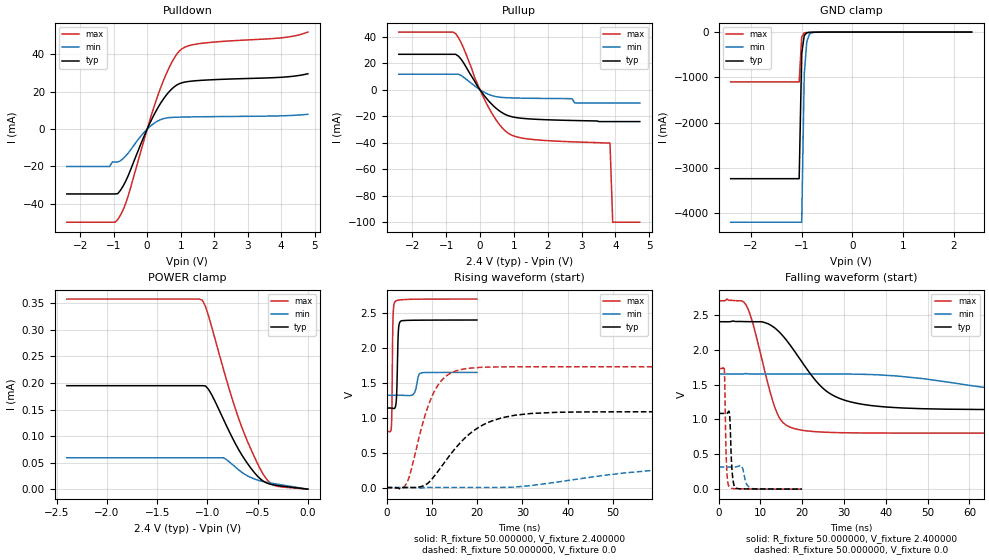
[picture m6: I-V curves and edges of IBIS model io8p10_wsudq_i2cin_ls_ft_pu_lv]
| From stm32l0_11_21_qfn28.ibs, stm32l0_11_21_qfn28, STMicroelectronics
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|   Model io8p10_wsudq_i2cin_ls_ft_pu_lv
[Model]  io8p10_wsudq_i2cin_ls_ft_pu_lv
Model_type I/O
Polarity   Non-Inverting
Enable   Active-Low
Vinl =   0.720000V
Vinh =   1.680000V
Vmeas =  1.200000V
Cref =   50.000000pF
Rref =   100.000000M
Vref =   0.0V
C_comp   2.943600pF   2.919700pF   2.965100pF
[Temperature Range]   25.000000   0.105000k   -40.000000
[Pullup Reference]   2.400000V   1.650000V   2.700000V
[Pulldown Reference]   0.0V   0.0V   0.0V
[POWER Clamp Reference]   2.400000V   1.650000V   2.700000V
[GND Clamp Reference]   0.0V   0.0V   0.0V
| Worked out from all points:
|   slope of the pulldown table from 0 to 0.36 V, typ, clamps not added: 28.5 ohm
|   slope of the pullup table from 0 to 0.36 V, typ, clamps not added: 32.2 ohm
|   GND clamp passes 1 mA (typ) near -0.65 V on its own axis
|   rising waveform, R_fixture 50.000000, V_fixture 2.400000: 20-80 % time 285ps typ, 637ps min, 195ps max; typ from 1.14 V to 2.4 V
|   rising waveform, R_fixture 50.000000, V_fixture 0.0: 20-80 % time 9.34ns typ, 24.6ns min, 4.81ns max; typ from 0.001 V to 1.09 V
|   falling waveform, R_fixture 50.000000, V_fixture 2.400000: 20-80 % time 10ns typ, 27.9ns min, 4.95ns max; typ from 2.4 V to 1.14 V
|   falling waveform, R_fixture 50.000000, V_fixture 0.0: 20-80 % time 486ps typ, 847ps min, 387ps max; typ from 1.09 V to 0.001 V
[Pulldown]
|Voltage   I(typ)   I(min)   I(max)
-2.4V     -34.7mA    -20mA      -49.82mA
-1.12V    -34.7mA    -20mA      -49.82mA
-1.04V    -34.7mA    -17.61mA   -49.82mA
-880mV    -34.55mA   -17.61mA   -48.46mA
-560mV    -24.65mA   -12.68mA   -35.33mA
0V        0A         0A         0A
400mV     13.84mA    5.066mA    22.03mA
720mV     21.25mA    6.254mA    35.26mA
1.04V     24.83mA    6.464mA    43.02mA
1.6V      26.11mA    6.627mA    45.88mA
4V        27.76mA    7.125mA    48.87mA
4.8V      29.63mA    7.94mA     51.96mA
[Pullup]
|Voltage   I(typ)   I(min)   I(max)
-2.4V     26.83mA    11.83mA    43.61mA
-720mV    26.83mA    11.83mA    42.44mA
-480mV    20.19mA    9.416mA    31.24mA
-160mV    6.617mA    3.074mA    9.467mA
240mV     -7.917mA   -3.299mA   -12.65mA
560mV     -15.67mA   -5.497mA   -25.76mA
880mV     -19.92mA   -6.062mA   -33.51mA
1.68V     -22.29mA   -6.449mA   -37.81mA
2.8V      -23.2mA    -10mA      -39.35mA
3.84V     -24mA      -10mA      -40.2mA
3.92V     -24mA      -10mA      -100mA
4.72V     -24mA      -10mA      -100mA
[GND_clamp]
|Voltage   I(typ)   I(min)   I(max)
-2.4V     -3.237A    -4.198A    -1.1A
-1.05V    -3.237A    -4.198A    -1.1A
-1V       -475.8mA   -4.198A    -104.2mA
-950mV    -76.24mA   -935.4mA   -18.39mA
-900mV    -16.61mA   -212.9mA   -9.105mA
-850mV    -6.547mA   -50.94mA   -6.589mA
-800mV    -3.998mA   -13.81mA   -4.86mA
-650mV    -1.043mA   -1.182mA   -1.146mA
2.35V     0A         0A         0A
[POWER_clamp]
|Voltage   I(typ)   I(min)   I(max)
-2.4V     195uA      59.14uA    358.2uA
-1.05V    195uA      59.14uA    356uA
-1.02V    194.5uA    59.14uA    344.5uA
-960mV    178.7uA    59.14uA    307.4uA
-840mV    131.4uA    59.14uA    225.5uA
-690mV    74.82uA    36.58uA    133.7uA
-600mV    48.08uA    24.92uA    89.53uA
-510mV    26.23uA    17.69uA    51.64uA
-450mV    15.91uA    14.53uA    29.77uA
-390mV    10.19uA    12.23uA    14.39uA
-330mV    7.608uA    10.24uA    6.963uA
0V        0A         0A         0A
[Ramp]
| variable   typ   min   max
dV/dt_r  0.65095/9.32887n   0.19037/24.57509n   1.03799/4.79707n
dV/dt_f  0.75618/10.03745n   0.19644/27.86319n   1.13779/4.93680n
R_load = 50.000000
[Rising Waveform]
R_fixture= 50.000000
V_fixture= 2.400000
V_fixture_min= 1.650000
V_fixture_max= 2.700000
|time   V(typ)   V(min)   V(max)
0s        1.14V      1.323V     803.7mV
1.041ns   1.139V     1.323V     868.9mV
1.161ns   1.138V     1.323V     1.181V
1.401ns   1.135V     1.323V     2.437V
1.842ns   1.144V     1.323V     2.662V
2.202ns   1.338V     1.323V     2.679V
2.603ns   2.26V      1.323V     2.685V
3.003ns   2.378V     1.323V     2.688V
7.648ns   2.398V     1.643V     2.699V
19.94ns   2.4V       1.65V      2.7V
[Rising Waveform]
R_fixture= 50.000000
V_fixture= 0.0
V_fixture_min= 0.0
V_fixture_max= 0.0
|time   V(typ)   V(min)   V(max)
0s        880.3uV    1.329mV    513.8uV
4.505ns   1.736mV    1.424mV    71.86mV
8.509ns   39.47mV    1.563mV    1.041V
11.51ns   248.6mV    2.317mV    1.485V
14.51ns   509.7mV    2.315mV    1.651V
18.52ns   779.7mV    2.361mV    1.712V
25.53ns   1.001V     3.404mV    1.729V
38.04ns   1.079V     82.83mV    1.73V
86.09ns   1.086V     310.2mV    1.73V
249.2ns   1.086V     318.6mV    1.73V
[Falling Waveform]
R_fixture= 50.000000
V_fixture= 2.400000
V_fixture_min= 1.650000
V_fixture_max= 2.700000
|time   V(typ)   V(min)   V(max)
0s        2.4V       1.65V      2.7V
6.507ns   2.402V     1.657V     2.646V
8.008ns   2.401V     1.651V     2.415V
14.01ns   2.281V     1.65V      1.087V
16.52ns   2.113V     1.65V      905.9mV
21.02ns   1.73V      1.65V      836.3mV
29.03ns   1.299V     1.65V      810.4mV
44.04ns   1.164V     1.614V     804.1mV
91.09ns   1.14V      1.353V     803.7mV
249.2ns   1.14V      1.323V     803.7mV
[Falling Waveform]
R_fixture= 50.000000
V_fixture= 0.0
V_fixture_min= 0.0
V_fixture_max= 0.0
|time   V(typ)   V(min)   V(max)
0s        1.086V     318.6mV    1.73V
1.321ns   1.086V     318.6mV    1.746V
1.441ns   1.086V     318.6mV    1.593V
1.682ns   1.085V     318.6mV    790.2mV
1.882ns   1.085V     318.6mV    373.9mV
2.523ns   1.11V      318.6mV    36.46mV
3.203ns   273.4mV    318.4mV    11.27mV
3.924ns   25.88mV    318.3mV    7.365mV
7.928ns   3.713mV    10.67mV    2.498mV
19.94ns   880.3uV    1.329mV    513.8uV
